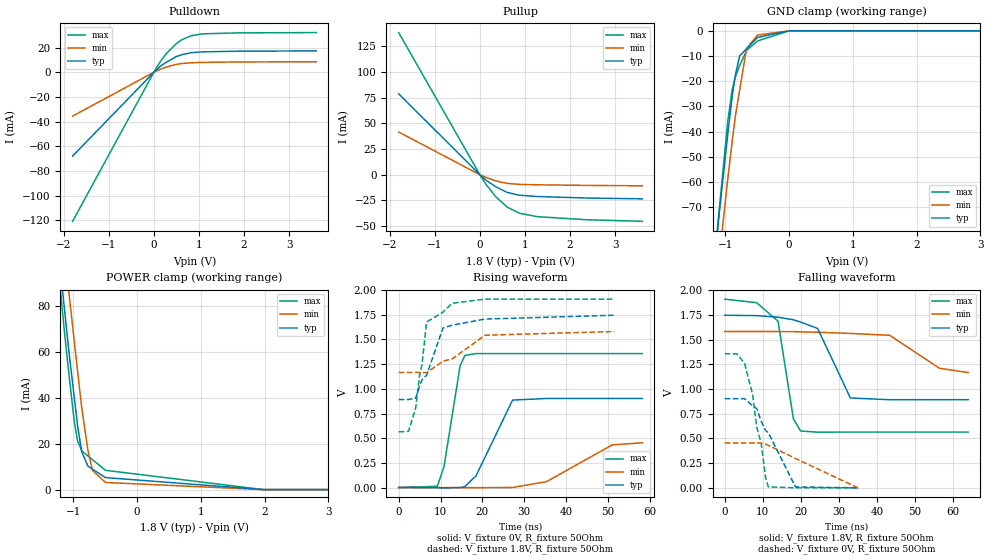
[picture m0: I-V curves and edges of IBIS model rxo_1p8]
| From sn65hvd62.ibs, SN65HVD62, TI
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|   rxo_1p8 Model
[Model]   rxo_1p8
Model_type   3-state
Polarity   Non-Inverting
Vmeas = 0.9
Vref = 0.9
Cref = 2pF
Rref = 50
|   typ   min   max
|   (nom PVT)   (fast PVT)   (slow PVT)
C_comp   2.314e-12   2.181e-12   2.539e-12
|ON state : BUFFER OUTPUT TURNED HIGH
|C_comp   2.314e-12   2.181e-12   2.539e-12
|OFF state: BUFFER IN HIGH IMPEDANCE
|C_comp   1.903e-12   1.883e-12   1.924e-12
| Where nom  PVT is Nominal Process, 1.8V, 27C
|   Fast PVT is Strong Process,  1.98V, -40C
|   Slow PVT is Weak Process,   1.62V, 125C
[Voltage Range]   1.8   1.62   1.98
|Ambient Temperature   25   85   -40
|Junction Temperature
[Temperature Range]   27   125   -40
[Pullup Reference]   1.8   1.62   1.98
[Pulldown Reference]   0   0   0
[Power Clamp Reference]   1.8   1.62   1.98
[GND Clamp Reference]   0   0   0
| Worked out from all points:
|   slope of the pulldown table from 0 to 0.27 V, typ, clamps not added: 34 ohm
|   slope of the pullup table from 0 to 0.27 V, typ, clamps not added: 28.7 ohm
|   GND clamp passes 1 mA (typ) near -0.22 V on its own axis
|   falling waveform, V_fixture 1.8V, R_fixture 50Ohm: 20-80 % time 5.38ns typ, 9.52ns min, 3.11ns max; typ from 1.75 V to 0.892 V
|   rising waveform, V_fixture 0V, R_fixture 50Ohm: 20-80 % time 5.61ns typ, 11.3ns min, 2.98ns max; typ from 0 V to 0.902 V
|   rising waveform, V_fixture 1.8V, R_fixture 50Ohm: 20-80 % time 4.97ns typ, 9.47ns min, 2.28ns max; typ from 0.892 V to 1.75 V
|   falling waveform, V_fixture 0V, R_fixture 50Ohm: 20-80 % time 7.38ns typ, 13.6ns min, 3.97ns max; typ from 0.902 V to 0 V
[Pulldown]
|   Voltage   I(typ)   I(min)   I(max)
-1.8V     -67.98mA   -35.58mA   -120.9mA
11.88mV   416uA      214.2uA    777.5uA
156.4mV   5.193mA    2.663mA    9.304mA
269.3mV   7.928mA    4.204mA    14.83mA
499mV     12.75mA    6.41mA     23.29mA
623.7mV   14.31mA    7.127mA    26.46mA
823.7mV   15.83mA    7.699mA    29.65mA
1.069V    16.56mA    8.011mA    31.15mA
1.869V    17.11mA    8.35mA     31.97mA
3.6V      17.36mA    8.563mA    32.21mA
[GND Clamp]
|   Voltage   I(typ)   I(min)   I(max)
-1.8V     -278.5mA   -271.6mA   -299.4mA
-1.119V   -79.11mA   -96.03mA   -77.36mA
-1.091V   -71.63mA   -89.44mA   -70.02mA
-960.3mV  -40.97mA   -58.69mA   -35.85mA
-891mV    -25.93mA   -43.76mA   -23.32mA
-842.4mV  -17.52mA   -33.99mA   -18.44mA
-774mV    -9.943mA   -23.45mA   -13.7mA
-675.5mV  -7.365mA   -8.27mA    -8.501mA
-659.3mV  -6.941mA   -6.827mA   -7.645mA
-494.1mV  -2.63mA    -1.694mA   -4.009mA
-29.03fV  0A         0A         0A
3.6V      0A         0A         0A
[Pullup]
|   Voltage   I(typ)   I(min)   I(max)
-1.8V     78.8mA     41.59mA    138.4mA
9.9mV     -396.9uA   -212.1uA   -728.9uA
132.7mV   -5.164mA   -2.531mA   -9.159mA
348.5mV   -11.63mA   -5.981mA   -21.31mA
601.9mV   -17.2mA    -8.411mA   -31.38mA
871.2mV   -19.95mA   -9.414mA   -37.47mA
1.277V    -21.26mA   -9.842mA   -40.87mA
2.376V    -22.71mA   -10.42mA   -43.87mA
3.6V      -23.51mA   -10.79mA   -45.37mA
[POWER Clamp]
|   Voltage   I(typ)   I(min)   I(max)
-1.8V     276.1mA    291.2mA    272.9mA
-1.271V   115.5mA    141.3mA    107.2mA
-1.136V   78.33mA    103mA      68.39mA
-1.075V   62.01mA    87.69mA    52.24mA
-982.1mV  39.89mA    64.44mA    29.49mA
-930.6mV  27.7mA     51.5mA     21.19mA
-865.8mV  16.43mA    35.48mA    16.89mA
-767.9mV  10.18mA    16.79mA    14.65mA
-698.2mV  8.92mA     8.386mA    13.06mA
-494.1mV  5.231mA    3.106mA    8.407mA
1.982V    0A         0A         0A
3.6V      0A         0A         0A
[Ramp]
R_load = 50
|   typ   min   max
dV/dt_r   0.541314/5.62236e-09   0.272211/1.12292e-08   0.814118/2.97644e-09
dV/dt_f   0.512345/5.3785e-09   0.24983/9.43438e-09   0.806714/3.09863e-09
[Falling Waveform]
V_fixture = 1.8V
V_fixture_min = 1.62V
V_fixture_max = 1.98V
R_fixture = 50Ohm
|   Time   V(typ)   V(min)   V(max)
0s        1.746V     1.582V     1.909V
8.38ns    1.742V     1.582V     1.873V
14ns      1.726V     1.581V     1.686V
18.03ns   1.7V       1.58V      697.9mV
19.92ns   1.677V     1.578V     575mV
24.39ns   1.612V     1.574V     563.3mV
32.98ns   909.2mV    1.562V     564.4mV
43.31ns   891.6mV    1.543V     564.3mV
56.32ns   891.7mV    1.21V      564.3mV
63.91ns   891.7mV    1.166V     564.3mV
[Rising Waveform]
V_fixture = 0V
V_fixture_min = 0V
V_fixture_max = 0V
R_fixture = 50Ohm
|   Time   V(typ)   V(min)   V(max)
0s        3.698nV    32.03nV    2.446nV
9.23ns    -1.642mV   -957.4uV   12.23mV
10.82ns   -3.528mV   -884.4uV   209.6mV
14.67ns   -235.1uV   -1.542mV   1.231V
15.82ns   8.995mV    -1.441mV   1.339V
18.48ns   118.6mV    -1.248mV   1.357V
27.22ns   886.1mV    23.79uV    1.357V
35.32ns   902.2mV    59.32mV    1.357V
51.02ns   902.2mV    431.9mV    1.357V
58.19ns   902.2mV    453.4mV    1.357V
[Rising Waveform]
V_fixture = 1.8V
V_fixture_min = 1.62V
V_fixture_max = 1.98V
R_fixture = 50Ohm
|   Time   V(typ)   V(min)   V(max)
0s        891.7mV    1.166V     564.3mV
2.36ns    891.7mV    1.166V     568.9mV
4.07ns    904.8mV    1.166V     805mV
4.96ns    1.022V     1.166V     1.125V
5.56ns    1.091V     1.166V     1.242V
6.68ns    1.138V     1.164V     1.677V
10.58ns   1.616V     1.28V      1.777V
12.78ns   1.645V     1.303V     1.867V
20.63ns   1.707V     1.543V     1.909V
51.53ns   1.746V     1.581V     1.909V
[Falling Waveform]
V_fixture = 0V
V_fixture_min = 0V
V_fixture_max = 0V
R_fixture = 50Ohm
|   Time   V(typ)   V(min)   V(max)
0s        902.2mV    453.7mV    1.357V
3.22ns    902.2mV    453.7mV    1.355V
5.21ns    902.8mV    453.7mV    1.26V
7.32ns    829.1mV    453.7mV    946mV
8.43ns    800.7mV    453.7mV    611.7mV
9.56ns    676.3mV    454.1mV    452.4mV
10.75ns   579.3mV    442.3mV    103.2mV
11.43ns   559.7mV    430.7mV    10.27mV
18.58ns   9.551mV    297.3mV    228.1uV
34.98ns   2.59nV     43.16nV    51.49pV
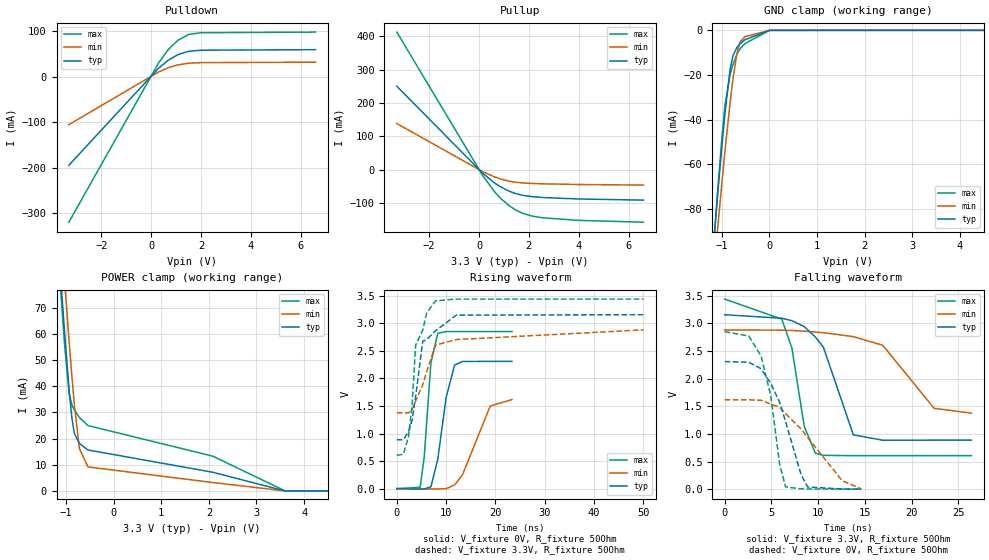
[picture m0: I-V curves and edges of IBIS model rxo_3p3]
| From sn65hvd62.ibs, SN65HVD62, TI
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|   rxo_3p3 Model
[Model]   rxo_3p3
Model_type   3-state
Polarity   Non-Inverting
Vmeas = 1.65
Vref = 1.65
Cref = 2pF
Rref = 50
|   typ   min   max
|   (nom PVT)   (fast PVT)   (slow PVT)
 C_comp   2.656e-12   2.476e-12   2.994e-12
|ON state : BUFFER OUTPUT TURNED HIGH
|C_comp   2.656e-12   2.476e-12   2.994e-12
|OFF state: BUFFER IN HIGH IMPEDANCE
|C_comp   1.720e-12   1.702e-12   1.729e-12
| Where nom  PVT is Nominal Process, 3.3V, 27C
|   Fast PVT is Strong Process,  3.6V, -40C
|   Slow PVT is Weak Process,   3V, 125C
[Voltage Range]   3.3   3   3.6
|Ambient Temperature   25   85   -40
|Junction Temperature
[Temperature Range]   27   125   -40
[Pullup Reference]   3.3   3   3.6
[Pulldown Reference]   0   0   0
[Power Clamp Reference]   3.3   3   3.6
[GND Clamp Reference]   0   0   0
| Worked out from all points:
|   slope of the pulldown table from 0 to 0.495 V, typ, clamps not added: 17.9 ohm
|   slope of the pullup table from 0 to 0.495 V, typ, clamps not added: 15.1 ohm
|   GND clamp passes 1 mA (typ) near -0.13 V on its own axis
|   falling waveform, V_fixture 3.3V, R_fixture 50Ohm: 20-80 % time 2.6ns typ, 4.04ns min, 1.92ns max; typ from 3.16 V to 0.887 V
|   rising waveform, V_fixture 0V, R_fixture 50Ohm: 20-80 % time 2.28ns typ, 4.24ns min, 1.36ns max; typ from 0 V to 2.31 V
|   rising waveform, V_fixture 3.3V, R_fixture 50Ohm: 20-80 % time 2.37ns typ, 3.48ns min, 2.57ns max; typ from 0.888 V to 3.16 V
|   falling waveform, V_fixture 0V, R_fixture 50Ohm: 20-80 % time 2.62ns typ, 4.93ns min, 1.62ns max; typ from 2.31 V to 0 V
[Pulldown]
|   Voltage   I(typ)   I(min)   I(max)
-3.3V     -194.4mA   -105.4mA   -319.1mA
306mV     18.44mA    9.978mA    30.3mA
693mV     35.98mA    19.37mA    59.3mA
1.083V    47.96mA    25.58mA    79.53mA
1.499V    55.13mA    29.06mA    91.99mA
2.003V    57.63mA    30.38mA    95.91mA
6.6V      58.77mA    31.34mA    97.28mA
[GND Clamp]
|   Voltage   I(typ)   I(min)   I(max)
-3.3V     -777mA     -713.6mA   -858.9mA
-1.161V   -92.22mA   -106.3mA   -93.06mA
-1.086V   -72.87mA   -88.14mA   -71.3mA
-993mV    -50.28mA   -66.76mA   -46.54mA
-934.8mV  -37.15mA   -54.02mA   -33.36mA
-825mV    -17.14mA   -31.92mA   -19.49mA
-765.6mV  -11.32mA   -21.5mA    -15.26mA
-682.8mV  -7.624mA   -10.2mA    -10.73mA
-615mV    -5.857mA   -5.194mA   -8.22mA
-510mV    -4.155mA   -2.779mA   -5.882mA
1.2mV     0A         0A         -13.24uA
6.6V      0A         0A         0A
[Pullup]
|   Voltage   I(typ)   I(min)   I(max)
-3.3V     250.2mA    138.2mA    412.3mA
163.2mV   -11.86mA   -6.533mA   -19.57mA
638.4mV   -40.77mA   -22.21mA   -67.49mA
870mV     -51.86mA   -28.06mA   -86.15mA
1.175V    -63.55mA   -33.97mA   -106.2mA
1.438V    -71.03mA   -37.48mA   -119.6mA
1.734V    -76.73mA   -39.83mA   -130.5mA
2.143V    -81.03mA   -41.46mA   -139.4mA
2.568V    -83.58mA   -42.51mA   -144.4mA
3.983V    -87.9mA    -44.48mA   -152mA
6.6V      -91.37mA   -46.25mA   -157.5mA
[POWER Clamp]
|   Voltage   I(typ)   I(min)   I(max)
-3.3V     766mA      752.2mA    797.3mA
-1.165V   95.76mA    114.8mA    91.56mA
-1.108V   80.37mA    99.85mA    75.64mA
-1.032V   60.94mA    80.61mA    56.1mA
-934.8mV  38.38mA    56.92mA    37.2mA
-874.5mV  27.49mA    43.19mA    32.71mA
-825mV    22.01mA    32.85mA    30.95mA
-720mV    18.16mA    16.27mA    28.1mA
-540mV    15.65mA    9.191mA    24.98mA
2.085V    7.127mA    3.201mA    13.27mA
3.598V    0A         0A         26.47uA
6.6V      0A         0A         0A
[Ramp]
R_load = 50
|   typ   min   max
dV/dt_r   1.3868/2.28248e-09   0.970915/4.22692e-09   1.71122/1.36046e-09
dV/dt_f   1.36201/2.5895e-09   0.903616/4.0308e-09   1.70106/1.90937e-09
[Falling Waveform]
V_fixture = 3.3V
V_fixture_min = 3V
V_fixture_max = 3.6V
R_fixture = 50Ohm
|   Time   V(typ)   V(min)   V(max)
0s        3.158V     2.883V     3.442V
6.11ns    3.095V     2.879V     3.078V
7.19ns    3.05V      2.873V     2.555V
8.505ns   2.944V     2.86V      1.138V
9.695ns   2.755V     2.846V     651mV
10.55ns   2.575V     2.833V     612.4mV
13.76ns   983.6mV    2.762V     606.3mV
16.91ns   885.8mV    2.605V     606.7mV
22.4ns    887.5mV    1.464V     606.7mV
26.39ns   887.5mV    1.376V     606.7mV
[Rising Waveform]
V_fixture = 0V
V_fixture_min = 0V
V_fixture_max = 0V
R_fixture = 50Ohm
|   Time   V(typ)   V(min)   V(max)
0s        4.162nV    26.36nV    2.84nV
4.73ns    -9.726mV   -3.014mV   24mV
5.555ns   -6.526mV   -5.547mV   567.6mV
6.915ns   32.91mV    -5.679mV   2.279V
8.295ns   525.2mV    -6.773mV   2.82V
10ns      1.653V     -244.8uV   2.852V
11.71ns   2.243V     65mV       2.852V
13.3ns    2.309V     247.9mV    2.852V
18.94ns   2.311V     1.5V       2.852V
23.35ns   2.311V     1.617V     2.852V
[Rising Waveform]
V_fixture = 3.3V
V_fixture_min = 3V
V_fixture_max = 3.6V
R_fixture = 50Ohm
|   Time   V(typ)   V(min)   V(max)
0s        887.5mV    1.377V     606.8mV
1.33ns    887.5mV    1.377V     623mV
2.385ns   1.035V     1.376V     943.1mV
3.105ns   1.242V     1.431V     1.531V
3.83ns    1.675V     1.595V     2.61V
5.255ns   2.675V     1.882V     2.877V
6.055ns   2.707V     2.123V     3.187V
7.86ns    2.866V     2.607V     3.411V
12.06ns   3.15V      2.706V     3.442V
50ns      3.158V     2.883V     3.442V
[Falling Waveform]
V_fixture = 0V
V_fixture_min = 0V
V_fixture_max = 0V
R_fixture = 50Ohm
|   Time   V(typ)   V(min)   V(max)
0s        2.311V     1.618V     2.852V
2.585ns   2.298V     1.618V     2.772V
3.895ns   2.18V      1.61V      2.41V
4.925ns   1.917V     1.54V      1.693V
5.885ns   1.569V     1.48V      441mV
6.52ns    1.22V      1.365V     39.48mV
8.17ns    262.8mV    1.09V      5.974mV
8.875ns   38.93mV    934.6mV    4.612mV
12.57ns   3.946mV    152.6mV    -27.04uV
14.61ns   239.1uV    6.332mV    -886nV
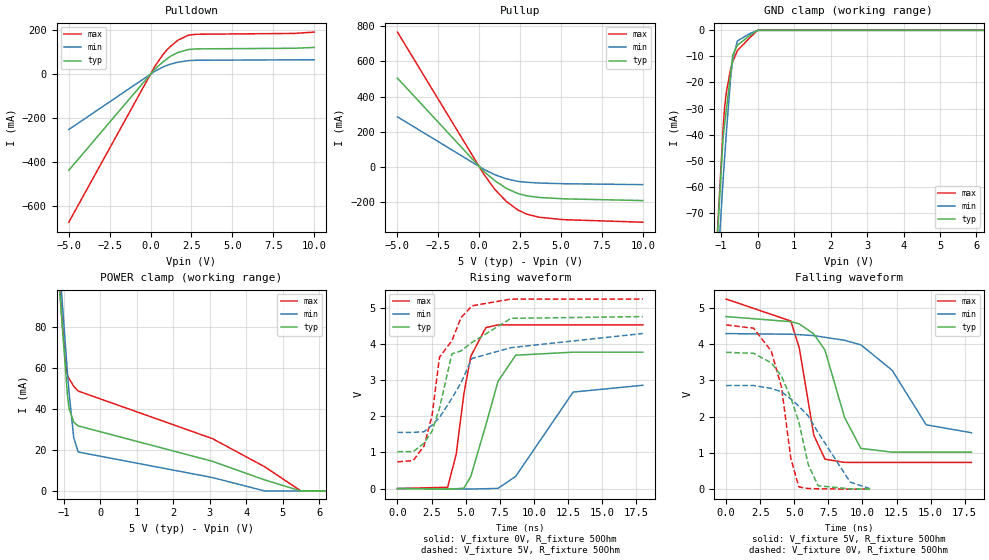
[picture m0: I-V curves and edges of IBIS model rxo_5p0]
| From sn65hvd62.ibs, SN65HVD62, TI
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|   rxo_5p0 Model
[Model]   rxo_5p0
Model_type   3-state
Polarity   Non-Inverting
Vmeas = 2.5
Vref = 2.5
Cref = 2pF
Rref = 50
|   typ   min   max
|   (nom PVT)   (fast PVT)   (slow PVT)
 C_comp   2.726e-12   2.523e-12   3.166e-12
|ON state : BUFFER OUTPUT TURNED HIGH
|C_comp   2.726e-12   2.523e-12   3.166e-12
|OFF state: BUFFER IN HIGH IMPEDANCE
|C_comp   1.569e-12   1.561e-12   1.585e-12
| Where nom  PVT is Nominal Process, 5V, 27C
|   Fast PVT is Strong Process,  5.5V, -40C
|   Slow PVT is Weak Process,   4.5V, 125C
[Voltage Range]   5   4.5   5.5
|Ambient Temperature   25   85   -40
|Junction Temperature
[Temperature Range]   27   125   -40
[Pullup Reference]   5   4.5   5.5
[Pulldown Reference]   0   0   0
[Power Clamp Reference]   5   4.5   5.5
[GND Clamp Reference]   0   0   0
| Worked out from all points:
|   slope of the pulldown table from 0 to 0.75 V, typ, clamps not added: 13.9 ohm
|   slope of the pullup table from 0 to 0.75 V, typ, clamps not added: 11.6 ohm
|   GND clamp passes 1 mA (typ) near -0.11 V on its own axis
|   falling waveform, V_fixture 5V, R_fixture 50Ohm: 20-80 % time 1.92ns typ, 2.88ns min, 1.29ns max; typ from 4.76 V to 1.02 V
|   rising waveform, V_fixture 0V, R_fixture 50Ohm: 20-80 % time 1.58ns typ, 2.85ns min, 1.08ns max; typ from 0 V to 3.78 V
|   rising waveform, V_fixture 5V, R_fixture 50Ohm: 20-80 % time 2.62ns typ, 2.39ns min, 2.05ns max; typ from 1.02 V to 4.76 V
|   falling waveform, V_fixture 0V, R_fixture 50Ohm: 20-80 % time 1.77ns typ, 3.02ns min, 1.22ns max; typ from 3.78 V to 0.001 V
[Pulldown]
|   Voltage   I(typ)   I(min)   I(max)
-5V       -438.6mA   -253.1mA   -674.8mA
264mV     22.33mA    12.16mA    34.71mA
759mV     54.5mA     31.39mA    88.1mA
968mV     66.36mA    37.48mA    106.6mA
1.205V    79.8mA     44.23mA    124.2mA
1.672V    97.49mA    53.47mA    153.5mA
2.316V    111.1mA    60.41mA    176.3mA
2.8V      113.9mA    62.11mA    180.4mA
8.794V    116.7mA    64.08mA    184.2mA
10V       120.5mA    64.58mA    190.3mA
[GND Clamp]
|   Voltage   I(typ)   I(min)   I(max)
-5V       -1.367A    -1.243A    -1.509A
-1.14V    -88.44mA   -102.2mA   -89.43mA
-1.089V   -75.98mA   -89.55mA   -73.95mA
-945mV    -40.79mA   -57.15mA   -37.45mA
-907.5mV  -36.35mA   -49.52mA   -29.91mA
-858mV    -30.5mA    -39.46mA   -23.71mA
-747mV    -17.37mA   -19.44mA   -15.36mA
-679.5mV  -9.391mA   -10.67mA   -11.93mA
-553.5mV  -5.691mA   -4.067mA   -7.74mA
-202.5mV  -1.885mA   -1.173mA   -2.685mA
-84.44fV  0A         0A         0A
10V       0A         0A         0A
[Pullup]
|   Voltage   I(typ)   I(min)   I(max)
-5V       504.5mA    284.4mA    766.8mA
280.5mV   -26.66mA   -14.77mA   -42.41mA
968mV     -80.49mA   -45.9mA    -130.6mA
1.672V    -124mA     -68.92mA   -198.9mA
2.376V    -152.9mA   -83.53mA   -246.6mA
2.909V    -165.5mA   -88.34mA   -270mA
3.691V    -175mA     -92.77mA   -287.9mA
5.192V    -182.7mA   -96.61mA   -301.4mA
10V       -192.5mA   -101.8mA   -315.6mA
[POWER Clamp]
|   Voltage   I(typ)   I(min)   I(max)
-5V       1.342A     1.295A     1.411A
-1.111V   97.31mA    109.9mA    99.2mA
-1.062V   85.54mA    96.92mA    86.53mA
-962.5mV  61.63mA    72.82mA    63.87mA
-905mV    47.82mA    58.89mA    56.97mA
-855mV    40.17mA    47.82mA    54.88mA
-729mV    33.66mA    26.16mA    51.16mA
-607.5mV  31.8mA     19.03mA    48.84mA
3.075V    14.48mA    6.534mA    25.57mA
4.505V    5.391mA    0A         11.83mA
5.495V    0A         0A         69.56uA
10V       0A         0A         0A
[Ramp]
R_load = 50
|   typ   min   max
dV/dt_r   2.26676/1.58042e-09   1.71661/2.84447e-09   2.72073/1.06997e-09
dV/dt_f   2.24526/1.92259e-09   1.64246/2.86772e-09   2.70567/1.28344e-09
[Falling Waveform]
V_fixture = 5V
V_fixture_min = 4.5V
V_fixture_max = 5.5V
R_fixture = 50Ohm
|   Time   V(typ)   V(min)   V(max)
0s        4.764V     4.295V     5.248V
4.748ns   4.624V     4.277V     4.642V
5.364ns   4.563V     4.265V     3.903V
6.432ns   4.285V     4.239V     1.49V
7.252ns   3.838V     4.192V     827.8mV
8.692ns   1.977V     4.109V     739.3mV
9.884ns   1.125V     3.985V     738.7mV
12.18ns   1.022V     3.282V     738.9mV
14.68ns   1.022V     1.776V     738.9mV
18ns      1.022V     1.558V     738.9mV
[Rising Waveform]
V_fixture = 0V
V_fixture_min = 0V
V_fixture_max = 0V
R_fixture = 50Ohm
|   Time   V(typ)   V(min)   V(max)
0s        4.886nV    25.04nV    3.509nV
3.684ns   -16.72mV   -9.843mV   36.79mV
4.312ns   -4.858mV   -8.801mV   957.2mV
4.872ns   9.386mV    -13.38mV   2.622V
5.38ns    336.5mV    -13.33mV   3.665V
6.484ns   1.76V      -3.802mV   4.458V
7.376ns   2.969V     5.667mV    4.533V
8.672ns   3.694V     337.2mV    4.535V
12.89ns   3.778V     2.673V     4.535V
18ns      3.778V     2.861V     4.535V
[Rising Waveform]
V_fixture = 5V
V_fixture_min = 4.5V
V_fixture_max = 5.5V
R_fixture = 50Ohm
|   Time   V(typ)   V(min)   V(max)
0s        1.022V     1.555V     739.5mV
1.152ns   1.022V     1.555V     776.2mV
1.952ns   1.257V     1.576V     1.18V
2.54ns    1.592V     1.758V     2.025V
3.084ns   2.226V     1.969V     3.638V
3.992ns   3.731V     2.498V     4.094V
4.66ns    3.812V     2.929V     4.733V
5.464ns   4.048V     3.603V     5.062V
8.328ns   4.715V     3.904V     5.249V
18ns      4.764V     4.295V     5.249V
[Falling Waveform]
V_fixture = 0V
V_fixture_min = 0V
V_fixture_max = 0V
R_fixture = 50Ohm
|   Time   V(typ)   V(min)   V(max)
0s        3.778V     2.861V     4.534V
2.016ns   3.75V      2.861V     4.443V
3.316ns   3.487V     2.781V     3.809V
4.06ns    3.119V     2.69V      2.818V
4.752ns   2.511V     2.488V     838.7mV
5.332ns   1.859V     2.292V     62.01mV
6.024ns   680.7mV    2.019V     16.8mV
6.744ns   94.91mV    1.566V     11.27mV
9.1ns     7.819mV    195.2mV    -39.62uV
10.57ns   660uV      10.11mV    -1.387uV
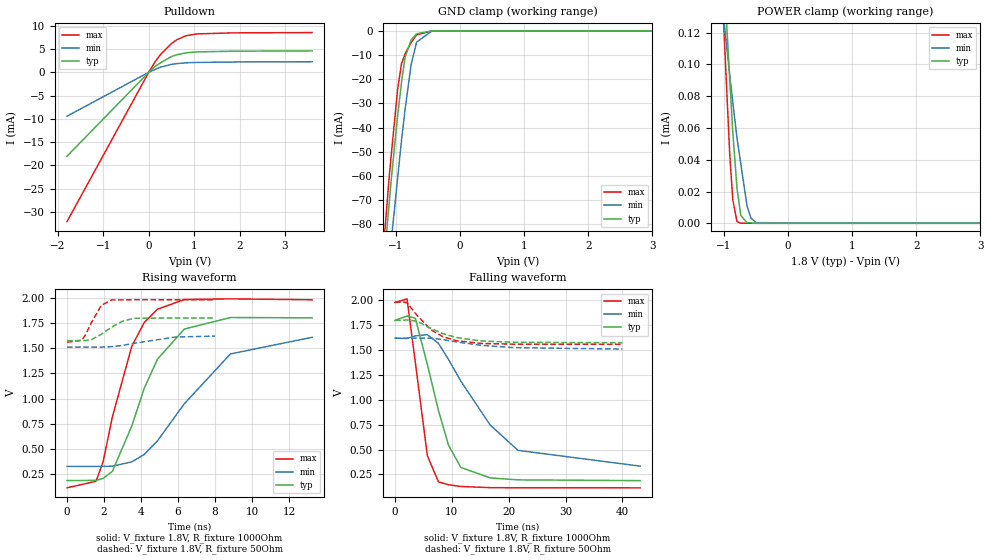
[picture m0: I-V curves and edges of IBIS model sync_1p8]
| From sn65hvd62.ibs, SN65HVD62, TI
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|   sync_1p8 Model
[Model]   sync_1p8
Model_type   Open_drain
Polarity   Non-Inverting
Vmeas = 0.9
Vref = 1.8
Cref = 2pF
Rref = 1000
|   typ   min   max
|   (nom PVT)   (fast PVT)   (slow PVT)
 C_comp   8.536e-13   8.321e-13   8.793e-13
|ON state : BUFFER OUTPUT TURNED LOW
|C_comp   8.536e-13   8.321e-13   8.793e-13
|OFF state: BUFFER IN HIGH IMPEDANCE
|C_comp   8.202e-13   8.028e-13   8.382e-13
| Where nom  PVT is Nominal Process, 1.8V, 27C
|   Fast PVT is Strong Process,  1.98V, -40C
|   Slow PVT is Weak Process,   1.62V, 125C
[Voltage Range]   1.8   1.62   1.98
|Ambient Temperature   25   85   -40
|Junction Temperature
[Temperature Range]   27   125   -40
[Pullup Reference]   1.8   1.62   1.98
[Pulldown Reference]   0   0   0
[Power Clamp Reference]   1.8   1.62   1.98
[GND Clamp Reference]   0   0   0
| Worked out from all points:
|   slope of the pulldown table from 0 to 0.27 V, typ, clamps not added: 128 ohm
|   GND clamp passes 1 mA (typ) near -0.63 V on its own axis
|   falling waveform, V_fixture 1.8V, R_fixture 1000Ohm: 20-80 % time 4.45ns typ, 9.44ns min, 2.44ns max; typ from 1.8 V to 0.188 V
|   rising waveform, V_fixture 1.8V, R_fixture 1000Ohm: 20-80 % time 2.08ns typ, 3.26ns min, 1.62ns max; typ from 0.188 V to 1.8 V
|   falling waveform, V_fixture 1.8V, R_fixture 50Ohm: 20-80 % time 6.25ns typ, 9.18ns min, 4.86ns max; typ from 1.8 V to 1.57 V
|   rising waveform, V_fixture 1.8V, R_fixture 50Ohm: 20-80 % time 1.13ns typ, 2.09ns min, 713ps max; typ from 1.57 V to 1.8 V
[Pulldown]
|   Voltage   I(typ)   I(min)   I(max)
-1.8V     -18mA      -9.418mA   -32.03mA
11.88mV   110.1uA    56.74uA    206uA
154.4mV   1.359mA    670.9uA    2.436mA
267.3mV   2.086mA    1.106mA    3.904mA
497mV     3.364mA    1.687mA    6.151mA
621.7mV   3.779mA    1.865mA    6.993mA
823.7mV   4.185mA    2.033mA    7.845mA
1.069V    4.376mA    2.115mA    8.24mA
1.869V    4.522mA    2.205mA    8.457mA
3.6V      4.589mA    2.261mA    8.519mA
[GND Clamp]
|   Voltage   I(typ)   I(min)   I(max)
-1.8V     -293.2mA   -298.1mA   -303.6mA
-1.262V   -118.8mA   -139.8mA   -112.8mA
-1.153V   -86.82mA   -109.4mA   -77.71mA
-1.097V   -70.14mA   -94.49mA   -59.42mA
-1.066V   -60.9mA    -86.26mA   -50.73mA
-970.2mV  -35.43mA   -61.18mA   -24.45mA
-908.8mV  -21.47mA   -45.35mA   -13.65mA
-853.2mV  -10.98mA   -32.59mA   -9.495mA
-758.2mV  -3.729mA   -13.88mA   -4.83mA
-673.2mV  -1.25mA    -4.659mA   -1.679mA
-434.2mV  -29.51uA   -55.89uA   -21.68uA
3.6V      0A         0A         0A
[POWER Clamp]
|   Voltage   I(typ)   I(min)   I(max)
-1.8V     820.3uA    447.9uA    969.8uA
-1.163V   287.1uA    191.8uA    287.7uA
-1.098V   236.4uA    166.5uA    223uA
-1.012V   168.2uA    133.7uA    136uA
-904.9mV  90.34uA    93.16uA    43.05uA
-857.3mV  57.09uA    76.02uA    14.74uA
-792mV    22.01uA    53.62uA    1.133uA
-732.6mV  4.939uA    37.36uA    65.4nA
-636.7mV  477nA      11.1uA     39.01nA
-575.1mV  270.2nA    3.29uA     22.08nA
-494.1mV  0A         407.9nA    0A
3.6V      0A         0A         0A
[Ramp]
R_load = 1000
|   typ   min   max
dV/dt_r   0.967491/2.07027e-09   0.775162/3.30546e-09   1.11889/1.61842e-09
dV/dt_f   0.967427/4.42914e-09   0.77482/9.46837e-09   1.11882/2.43133e-09
[Falling Waveform]
V_fixture = 1.8V
V_fixture_min = 1.62V
V_fixture_max = 1.98V
R_fixture = 1000Ohm
|   Time   V(typ)   V(min)   V(max)
0s        1.8V       1.62V      1.98V
2.108ns   1.844V     1.618V     2.016V
3.566ns   1.821V     1.644V     1.378V
5.684ns   1.356V     1.656V     438.6mV
7.64ns    892.5mV    1.568V     175.2mV
9.398ns   545.6mV    1.407V     146.6mV
11.57ns   320.7mV    1.189V     128.7mV
16.73ns   215.3mV    747.5mV    117.3mV
21.62ns   195.4mV    492.2mV    115.5mV
43.12ns   187.5mV    333.5mV    115.1mV
[Rising Waveform]
V_fixture = 1.8V
V_fixture_min = 1.62V
V_fixture_max = 1.98V
R_fixture = 1000Ohm
|   Time   V(typ)   V(min)   V(max)
0s        187.5mV    328mV      115.2mV
1.568ns   188.9mV    327.8mV    180.5mV
1.952ns   209.8mV    327.8mV    375.1mV
2.45ns    278.1mV    330.1mV    817.8mV
3.5ns     727.8mV    372.5mV    1.519V
4.172ns   1.102V     446.2mV    1.754V
4.886ns   1.39V      580.7mV    1.886V
6.344ns   1.69V      949.7mV    1.983V
8.834ns   1.804V     1.443V     1.989V
13.25ns   1.801V     1.608V     1.98V
[Falling Waveform]
V_fixture = 1.8V
V_fixture_min = 1.62V
V_fixture_max = 1.98V
R_fixture = 50Ohm
|   Time   V(typ)   V(min)   V(max)
0s        1.8V       1.62V      1.98V
1.322ns   1.8V       1.62V      1.987V
2.108ns   1.805V     1.62V      1.976V
3.866ns   1.791V     1.622V     1.85V
6.29ns    1.72V      1.62V      1.706V
8.366ns   1.667V     1.607V     1.637V
10.8ns    1.627V     1.583V     1.595V
15.1ns    1.593V     1.549V     1.568V
20.95ns   1.579V     1.525V     1.56V
40ns      1.575V     1.511V     1.559V
[Rising Waveform]
V_fixture = 1.8V
V_fixture_min = 1.62V
V_fixture_max = 1.98V
R_fixture = 50Ohm
|   Time   V(typ)   V(min)   V(max)
0s        1.575V     1.511V     1.559V
794ps     1.575V     1.511V     1.579V
992ps     1.575V     1.511V     1.63V
1.31ns    1.584V     1.511V     1.75V
1.838ns   1.636V     1.511V     1.921V
2.402ns   1.708V     1.515V     1.979V
2.984ns   1.766V     1.527V     1.979V
3.602ns   1.796V     1.548V     1.981V
5.828ns   1.8V       1.61V      1.98V
7.996ns   1.8V       1.62V      1.98V
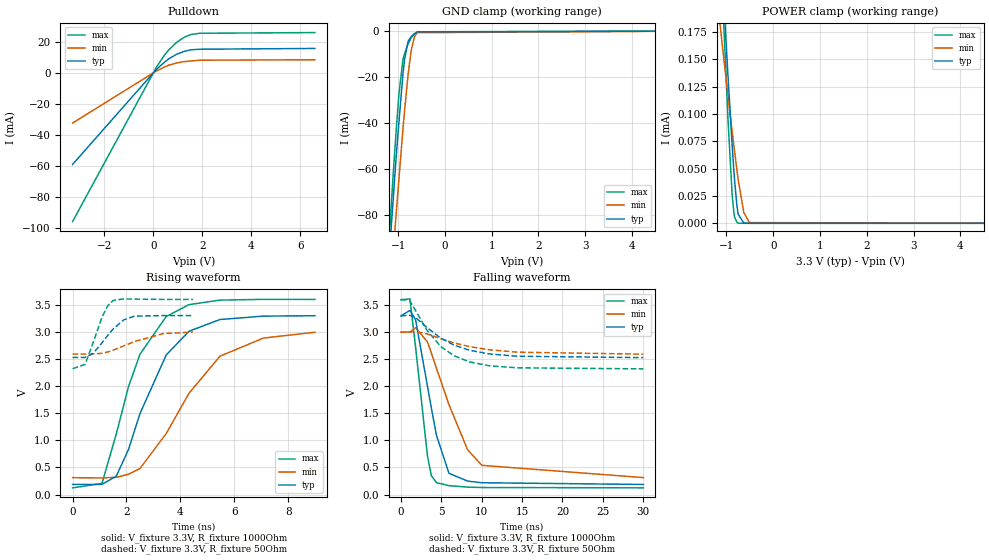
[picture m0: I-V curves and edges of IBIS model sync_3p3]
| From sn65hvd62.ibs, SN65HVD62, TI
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|   sync_3p3 Model
[Model]   sync_3p3
Model_type   Open_drain
Polarity   Non-Inverting
Vmeas = 1.65
Vref = 3.3
Cref = 2pF
Rref = 1000
|   typ   min   max
|   (nom PVT)   (fast PVT)   (slow PVT)
C_comp   8.028e-13   7.804e-13   8.291e-13
|ON state : BUFFER OUTPUT TURNED LOW
|C_comp   8.028e-13   7.804e-13   8.291e-13
|OFF state: BUFFER IN HIGH IMPEDANCE
|C_comp   7.537e-13   7.359e-13   7.723e-13
| Where nom  PVT is Nominal Process, 3.3V, 27C
|   Fast PVT is Strong Process,  3.6V, -40C
|   Slow PVT is Weak Process,   3V, 125C
[Voltage Range]   3.3   3   3.6
|Ambient Temperature   25   85   -40
|Junction Temperature
[Temperature Range]   27   125   -40
[Pullup Reference]   3.3   3   3.6
[Pulldown Reference]   0   0   0
[Power Clamp Reference]   3.3   3   3.6
[GND Clamp Reference]   0   0   0
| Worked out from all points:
|   slope of the pulldown table from 0 to 0.495 V, typ, clamps not added: 68.4 ohm
|   GND clamp passes 1 mA (typ) near -0.63 V on its own axis
|   falling waveform, V_fixture 3.3V, R_fixture 1000Ohm: 20-80 % time 2.31ns typ, 4.06ns min, 1.5ns max; typ from 3.3 V to 0.186 V
|   rising waveform, V_fixture 3.3V, R_fixture 1000Ohm: 20-80 % time 1.56ns typ, 2.08ns min, 1.34ns max; typ from 0.186 V to 3.3 V
|   falling waveform, V_fixture 3.3V, R_fixture 50Ohm: 20-80 % time 5.29ns typ, 6.75ns min, 4.4ns max; typ from 3.3 V to 2.53 V
|   rising waveform, V_fixture 3.3V, R_fixture 50Ohm: 20-80 % time 781ps typ, 1.29ns min, 540ps max; typ from 2.53 V to 3.3 V
[Pulldown]
|   Voltage   I(typ)   I(min)   I(max)
-3.3V     -59.09mA   -32.44mA   -95.85mA
136.8mV   2.296mA    1.182mA    3.825mA
478.8mV   7.038mA    3.847mA    11.78mA
633.6mV   8.928mA    4.809mA    14.71mA
939.6mV   11.71mA    6.164mA    19.37mA
1.246V    13.63mA    7.079mA    22.68mA
1.534V    14.69mA    7.506mA    24.54mA
1.89V     15.07mA    8.004mA    25.33mA
6.6V      15.57mA    8.302mA    25.78mA
[GND Clamp]
|   Voltage   I(typ)   I(min)   I(max)
-3.3V     -821.6mA   -781.7mA   -878.3mA
-1.208V   -102.4mA   -124.6mA   -95.47mA
-1.112V   -74.89mA   -98.09mA   -64.19mA
-1.044V   -55.18mA   -79.67mA   -43.73mA
-982.8mV  -39.5mA    -64.21mA   -27.4mA
-896.4mV  -18.57mA   -42.4mA    -12.3mA
-861.3mV  -12.21mA   -34.42mA   -9.876mA
-788.7mV  -4.629mA   -19.32mA   -5.694mA
-720mV    -2.423mA   -8.379mA   -2.927mA
-651mV    -1.354mA   -2.526mA   -1.254mA
-590.7mV  -420uA     -789.8uA   -533.3uA
6.6V      0A         0A         0A
[POWER Clamp]
|   Voltage   I(typ)   I(min)   I(max)
-3.3V     2.11mA     1.07mA     2.619mA
-1.238V   349.3uA    221.9uA    366.1uA
-1.176V   298.2uA    196.9uA    301.8uA
-1.08V    221.4uA    159.4uA    203uA
-968.4mV  135.3uA    116.7uA    95.67uA
-878.4mV  71.03uA    83.57uA    25.54uA
-831.6mV  41.78uA    67.37uA    6.178uA
-778.8mV  16.78uA    49.42uA    1.095uA
-748.8mV  8.173uA    39.81uA    143.9nA
-630mV    244.2nA    9.937uA    0A
-510mV    28nA       629.3nA    0A
6.6V      0A         0A         0A
[Ramp]
R_load = 1000
|   typ   min   max
dV/dt_r   1.86819/1.56114e-09   1.61289/2.08831e-09   2.08572/1.33819e-09
dV/dt_f   1.8681/2.29805e-09   1.61192/4.06007e-09   2.08565/1.49772e-09
[Falling Waveform]
V_fixture = 3.3V
V_fixture_min = 3V
V_fixture_max = 3.6V
R_fixture = 1000Ohm
|   Time   V(typ)   V(min)   V(max)
0s        3.3V       3V         3.6V
1.118ns   3.402V     3.004V     3.615V
1.82ns    3.228V     3.083V     2.718V
3.284ns   2.006V     2.82V      718.8mV
3.767ns   1.598V     2.617V     348.5mV
4.412ns   1.087V     2.328V     219.1mV
5.948ns   392mV      1.661V     164.5mV
8.252ns   248.9mV    828.1mV    137.2mV
10.01ns   218mV      539.9mV    130.2mV
30ns      186.4mV    313.3mV    123.7mV
[Rising Waveform]
V_fixture = 3.3V
V_fixture_min = 3V
V_fixture_max = 3.6V
R_fixture = 1000Ohm
|   Time   V(typ)   V(min)   V(max)
0s        186.3mV    311.7mV    123.8mV
1.091ns   188.3mV    306.5mV    205.1mV
1.622ns   338mV      318.6mV    1.116V
2.075ns   831.2mV    374mV      1.988V
2.504ns   1.496V     480.9mV    2.59V
3.476ns   2.575V     1.126V     3.284V
4.322ns   3.013V     1.868V     3.504V
5.471ns   3.229V     2.553V     3.587V
7.085ns   3.292V     2.887V     3.601V
8.998ns   3.299V     2.994V     3.6V
[Falling Waveform]
V_fixture = 3.3V
V_fixture_min = 3V
V_fixture_max = 3.6V
R_fixture = 50Ohm
|   Time   V(typ)   V(min)   V(max)
0s        3.3V       3V         3.6V
1.058ns   3.313V     3.001V     3.591V
1.757ns   3.277V     3.008V     3.415V
3.221ns   3.085V     2.97V      3.036V
4.919ns   2.891V     2.88V      2.737V
6.554ns   2.762V     2.802V     2.565V
8.486ns   2.666V     2.733V     2.45V
10.99ns   2.597V     2.673V     2.378V
14.4ns    2.555V     2.63V      2.341V
30ns      2.529V     2.593V     2.322V
[Rising Waveform]
V_fixture = 3.3V
V_fixture_min = 3V
V_fixture_max = 3.6V
R_fixture = 50Ohm
|   Time   V(typ)   V(min)   V(max)
0s        2.529V     2.592V     2.322V
467ps     2.53V      2.592V     2.401V
758ps     2.601V     2.592V     2.794V
1.094ns   2.799V     2.607V     3.276V
1.304ns   2.935V     2.63V      3.479V
1.505ns   3.053V     2.663V     3.581V
1.901ns   3.223V     2.743V     3.61V
2.297ns   3.291V     2.823V     3.605V
3.362ns   3.302V     2.969V     3.6V
4.472ns   3.301V     2.997V     3.6V
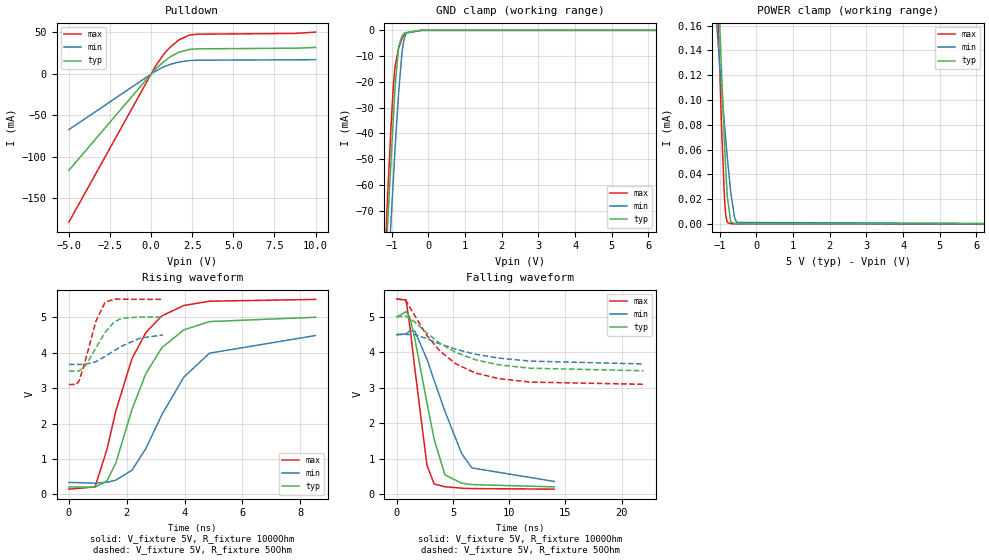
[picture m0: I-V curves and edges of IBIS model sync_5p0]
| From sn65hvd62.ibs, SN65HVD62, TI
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|   sync_5p0 Model
[Model]   sync_5p0
Model_type   Open_drain
Polarity   Non-Inverting
Vmeas = 2.5
Vref = 5
Cref = 2pF
Rref = 1000
|   typ   min   max
|   (nom PVT)   (fast PVT)   (slow PVT)
 C_comp   7.669e-13   7.434e-13   7.887e-13
|ON state : BUFFER OUTPUT TURNED LOW
|C_comp   7.669e-13   7.434e-13   7.887e-13
|OFF state: BUFFER IN HIGH IMPEDANCE
|C_comp   7.114e-13   6.950e-13   7.309e-13
| Where nom  PVT is Nominal Process, 5V, 27C
|   Fast PVT is Strong Process,  5.5V, -40C
|   Slow PVT is Weak Process,   4.5V, 125C
[Voltage Range]   5   4.5   5.5
|Ambient Temperature   25   85   -40
|Junction Temperature
[Temperature Range]   27   125   -40
[Pullup Reference]   5   4.5   5.5
[Pulldown Reference]   0   0   0
[Power Clamp Reference]   5   4.5   5.5
[GND Clamp Reference]   0   0   0
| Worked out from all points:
|   slope of the pulldown table from 0 to 0.75 V, typ, clamps not added: 52.4 ohm
|   GND clamp passes 1 mA (typ) near -0.63 V on its own axis
|   falling waveform, V_fixture 5V, R_fixture 1000Ohm: 20-80 % time 1.78ns typ, 2.88ns min, 1.23ns max; typ from 5 V to 0.215 V
|   rising waveform, V_fixture 5V, R_fixture 1000Ohm: 20-80 % time 1.39ns typ, 1.76ns min, 1.25ns max; typ from 0.211 V to 5 V
|   falling waveform, V_fixture 5V, R_fixture 50Ohm: 20-80 % time 4.92ns typ, 5.97ns min, 4.17ns max; typ from 5 V to 3.48 V
|   rising waveform, V_fixture 5V, R_fixture 50Ohm: 20-80 % time 672ps typ, 1.07ns min, 488ps max; typ from 3.48 V to 5 V
[Pulldown]
|   Voltage   I(typ)   I(min)   I(max)
-5V       -116.4mA   -67.32mA   -179mA
264mV     5.923mA    3.226mA    9.207mA
759mV     14.46mA    8.328mA    23.37mA
968mV     17.6mA     9.941mA    28.27mA
1.205V    21.17mA    11.73mA    32.94mA
1.672V    25.86mA    14.18mA    40.72mA
2.316V    29.45mA    16.02mA    46.76mA
2.8V      30.19mA    16.47mA    47.85mA
8.794V    30.94mA    16.99mA    48.82mA
10V       31.89mA    17.11mA    50.4mA
[GND Clamp]
|   Voltage   I(typ)   I(min)   I(max)
-5V       -1.444A    -1.355A    -1.548A
-1.14V    -82.23mA   -106.3mA   -73.35mA
-1.111V   -74.59mA   -98.12mA   -63.75mA
-1.023V   -51.4mA    -74.62mA   -37.84mA
-957mV    -34mA      -57.79mA   -21.57mA
-913mV    -22.41mA   -46.57mA   -14.16mA
-815mV    -6.518mA   -24.69mA   -7.121mA
-724.5mV  -2.338mA   -8.948mA   -3.322mA
-670mV    -1.203mA   -3.632mA   -1.753mA
-607.5mV  -891.2uA   -1.085mA   -1.02mA
-202.5mV  -5.463uA   -732.3nA   -3.232uA
10V       0A         0A         0A
[POWER Clamp]
|   Voltage   I(typ)   I(min)   I(max)
-5V       3.585mA    1.784mA    4.501mA
-1.111V   246.5uA    172.3uA    234.2uA
-1.028V   183.3uA    139.8uA    152.1uA
-1.008V   167.6uA    131.7uA    133uA
-946mV    120.1uA    108.5uA    75.95uA
-869mV    65.15uA    80.32uA    20.32uA
-836mV    44.57uA    68.83uA    7.28uA
-792mV    22.18uA    53.52uA    1.133uA
-700mV    1.67uA     25.63uA    234nA
-594mV    381.8nA    5.004uA    0A
-535.5mV  241.6nA    1.24uA     0A
10V       0A         0A         0A
[Ramp]
R_load = 1000
|   typ   min   max
dV/dt_r   2.87356/1.38846e-09   2.49673/1.76814e-09   3.21053/1.2469e-09
dV/dt_f   2.8733/1.78169e-09   2.49346/2.90259e-09   3.21052/1.22479e-09
[Falling Waveform]
V_fixture = 5V
V_fixture_min = 4.5V
V_fixture_max = 5.5V
R_fixture = 1000Ohm
|   Time   V(typ)   V(min)   V(max)
0s        5V         4.5V       5.5V
828ps     5.146V     4.516V     5.474V
1.166ns   4.99V      4.608V     4.728V
1.604ns   4.389V     4.597V     3.543V
2.684ns   2.576V     3.807V     828.5mV
3.33ns    1.547V     3.206V     294.8mV
4.28ns    553.5mV    2.346V     218.8mV
5.774ns   318.8mV    1.15V      177.3mV
6.688ns   278.4mV    747.2mV    166.9mV
14.01ns   215mV      367.5mV    149.9mV
[Rising Waveform]
V_fixture = 5V
V_fixture_min = 4.5V
V_fixture_max = 5.5V
R_fixture = 1000Ohm
|   Time   V(typ)   V(min)   V(max)
0s        210.5mV    338.1mV    149.1mV
906ps     203mV      318.9mV    211mV
1.32ns    387.5mV    343mV      1.283V
1.622ns   884.7mV    401.6mV    2.351V
2.178ns   2.388V     682.7mV    3.825V
2.66ns    3.405V     1.292V     4.564V
3.21ns    4.134V     2.242V     5.033V
3.972ns   4.641V     3.309V     5.328V
4.86ns    4.874V     3.983V     5.448V
8.526ns   4.996V     4.481V     5.499V
[Falling Waveform]
V_fixture = 5V
V_fixture_min = 4.5V
V_fixture_max = 5.5V
R_fixture = 50Ohm
|   Time   V(typ)   V(min)   V(max)
0s        5V         4.5V       5.5V
785ps     5.02V      4.504V     5.475V
1.574ns   4.864V     4.503V     5.046V
2.639ns   4.553V     4.389V     4.494V
3.848ns   4.254V     4.238V     4.033V
5.255ns   3.998V     4.087V     3.677V
6.98ns    3.793V     3.949V     3.42V
9.062ns   3.649V     3.838V     3.26V
11.91ns   3.553V     3.753V     3.163V
21.95ns   3.483V     3.674V     3.101V
[Rising Waveform]
V_fixture = 5V
V_fixture_min = 4.5V
V_fixture_max = 5.5V
R_fixture = 50Ohm
|   Time   V(typ)   V(min)   V(max)
0s        3.479V     3.667V     3.098V
257ps     3.478V     3.667V     3.105V
359ps     3.485V     3.667V     3.208V
572ps     3.624V     3.67V      3.786V
938ps     4.138V     3.746V     4.89V
1.25ns    4.568V     3.89V      5.418V
1.568ns   4.865V     4.056V     5.509V
1.835ns   4.972V     4.186V     5.505V
2.462ns   5.001V     4.407V     5.501V
3.251ns   5.001V     4.498V     5.5V
